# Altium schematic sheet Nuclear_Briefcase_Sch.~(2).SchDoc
size A; SheetNumber: 1; SheetTotal: 1

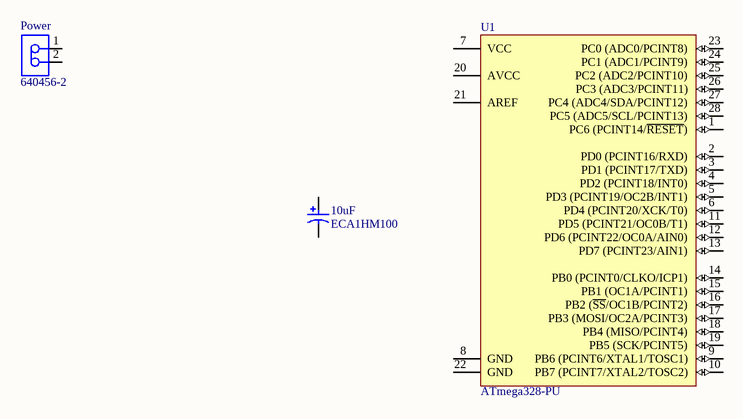
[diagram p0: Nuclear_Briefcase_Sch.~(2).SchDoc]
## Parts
10uF  ECA1HM100  [CAPPR55-200-1100X500X1200]
Power  640456-2  [TECO-640456-2_V]
U1  ATmega328-PU  [28P3]

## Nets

Not connected (* = marked no-connect by the designer): 10uF 1 2; Power 1 2; U1 1(PC6_(PCINT14/~{RESET})) 2(PD0_(PCINT16/RXD)) 3(PD1_(PCINT17/TXD)) 4(PD2_(PCINT18/INT0)) 5(PD3_(PCINT19/OC2B/INT1)) 6(PD4_(PCINT20/XCK/T0)) 7(VCC) 8(GND) 9(PB6_(PCINT6/XTAL1/TOSC1)) 10(PB7_(PCINT7/XTAL2/TOSC2)) 11(PD5_(PCINT21/OC0B/T1)) 12(PD6_(PCINT22/OC0A/AIN0)) 13(PD7_(PCINT23/AIN1)) 14(PB0_(PCINT0/CLKO/ICP1)) 15(PB1_(OC1A/PCINT1)) 16(PB2_(~{SS}/OC1B/PCINT2)) 17(PB3_(MOSI/OC2A/PCINT3)) 18(PB4_(MISO/PCINT4)) 19(PB5_(SCK/PCINT5)) 20(AVCC) 21(AREF) 22(GND) 23(PC0_(ADC0/PCINT8)) 24(PC1_(ADC1/PCINT9)) 25(PC2_(ADC2/PCINT10)) 26(PC3_(ADC3/PCINT11)) 27(PC4_(ADC4/SDA/PCINT12)) 28(PC5_(ADC5/SCL/PCINT13))

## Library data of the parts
10uF = CMP-1665-00038-2: Aluminum Electrolytic Capacitor, 10 uF, +/- 20%, 50 V, -40 to 85 degC, 2-Pin THD, RoHS, Bulk; Manufacturer: Panasonic; Life (Hours): 2000Hour; Lead/Base Style: Straight; Dissipation Factor: 0.12%; Capacitance: 10uF; Leakage Current: 3uA; Dielectric Material: Aluminium; Lead Diameter: 0.5mm; Voltage Rating: 50V; Ripple Current: 65mA
Power = CMP-2000-05417-1: Male Header, Pitch 2.54 mm, 1 x 2 Position, Height 10.49 mm, Tail Length 3.556 mm, -55 to 105 degC, RoHS, Bulk; Manufacturer: TE Connectivity; Standards: RoHSCompliant,ELVCompliant,UL94V-0; Material, Housing: Polyester; Agency Approvals: CSA,UL; Brand/Series: MTA-100Series; Contact Centerline Spacing: 0.100 / in.; Material, Contact: CopperAlloy; Current, Rating: 5 / A; Color, Housing: White; Contact Termination Area Plating: Tin; Special Features: Pinstrip; Number of Positions: 2; Pin Spacing: 0.1 / "; Temperature, Operating: -55to+105 / degC; Angle: Straight; Mount Angle: Vertical; Connector Type: MTA-100; Primary Type: InterconnectSystem; Voltage, Rating: 250 / V; Mounting Hole Size: 0.04 / "
U1 = CMP-0095-00015-2: 8-bit AVR Microcontroller, 32KB Flash, 1KB EEPROM, 2KB SRAM, 28-pin PDIP, Industrial Grade (-40°C to 85°C)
